VERSION 5.7 ;
  NOWIREEXTENSIONATPIN ON ;
  DIVIDERCHAR "/" ;
  BUSBITCHARS "[]" ;
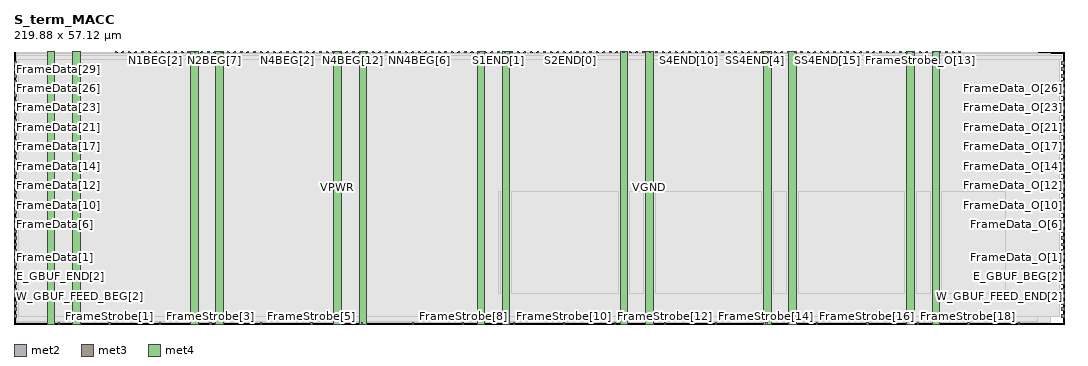
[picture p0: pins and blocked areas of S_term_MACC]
MACRO S_term_MACC
  CLASS BLOCK ;
  FOREIGN S_term_MACC ;
  ORIGIN 0.000 0.000 ;
  SIZE 219.880 BY 57.120 ;
  PIN CO
    DIRECTION OUTPUT ;
    USE SIGNAL ;
    PORT
      LAYER met2 ;
        RECT 98.530 56.840 98.810 57.120 ;
    END
  END CO
  PIN E_GBUF_BEG[0]
    DIRECTION OUTPUT ;
    USE SIGNAL ;
    ANTENNADIFFAREA 0.702900 ;
    PORT
      LAYER met3 ;
        RECT 219.280 6.840 219.880 7.440 ;
    END
  END E_GBUF_BEG[0]
  PIN E_GBUF_BEG[1]
    DIRECTION OUTPUT ;
    USE SIGNAL ;
    ANTENNADIFFAREA 0.702900 ;
    PORT
      LAYER met3 ;
        RECT 219.280 8.200 219.880 8.800 ;
    END
  END E_GBUF_BEG[1]
  PIN E_GBUF_BEG[2]
    DIRECTION OUTPUT ;
    USE SIGNAL ;
    ANTENNADIFFAREA 0.702900 ;
    PORT
      LAYER met3 ;
        RECT 219.280 9.560 219.880 10.160 ;
    END
  END E_GBUF_BEG[2]
  PIN E_GBUF_BEG[3]
    DIRECTION OUTPUT ;
    USE SIGNAL ;
    ANTENNADIFFAREA 0.702900 ;
    PORT
      LAYER met3 ;
        RECT 219.280 10.920 219.880 11.520 ;
    END
  END E_GBUF_BEG[3]
  PIN E_GBUF_END[0]
    DIRECTION INPUT ;
    USE SIGNAL ;
    ANTENNAGATEAREA 0.318000 ;
    PORT
      LAYER met3 ;
        RECT 0.000 6.840 0.600 7.440 ;
    END
  END E_GBUF_END[0]
  PIN E_GBUF_END[1]
    DIRECTION INPUT ;
    USE SIGNAL ;
    ANTENNAGATEAREA 0.318000 ;
    PORT
      LAYER met3 ;
        RECT 0.000 8.200 0.600 8.800 ;
    END
  END E_GBUF_END[1]
  PIN E_GBUF_END[2]
    DIRECTION INPUT ;
    USE SIGNAL ;
    ANTENNAGATEAREA 0.318000 ;
    PORT
      LAYER met3 ;
        RECT 0.000 9.560 0.600 10.160 ;
    END
  END E_GBUF_END[2]
  PIN E_GBUF_END[3]
    DIRECTION INPUT ;
    USE SIGNAL ;
    ANTENNAGATEAREA 0.318000 ;
    PORT
      LAYER met3 ;
        RECT 0.000 10.920 0.600 11.520 ;
    END
  END E_GBUF_END[3]
  PIN FrameData[0]
    DIRECTION INPUT ;
    USE SIGNAL ;
    ANTENNAGATEAREA 0.159000 ;
    PORT
      LAYER met3 ;
        RECT 0.000 12.280 0.600 12.880 ;
    END
  END FrameData[0]
  PIN FrameData[10]
    DIRECTION INPUT ;
    USE SIGNAL ;
    ANTENNAGATEAREA 0.159000 ;
    PORT
      LAYER met3 ;
        RECT 0.000 25.880 0.600 26.480 ;
    END
  END FrameData[10]
  PIN FrameData[11]
    DIRECTION INPUT ;
    USE SIGNAL ;
    ANTENNAGATEAREA 0.159000 ;
    PORT
      LAYER met3 ;
        RECT 0.000 27.240 0.600 27.840 ;
    END
  END FrameData[11]
  PIN FrameData[12]
    DIRECTION INPUT ;
    USE SIGNAL ;
    ANTENNAGATEAREA 0.159000 ;
    PORT
      LAYER met3 ;
        RECT 0.000 28.600 0.600 29.200 ;
    END
  END FrameData[12]
  PIN FrameData[13]
    DIRECTION INPUT ;
    USE SIGNAL ;
    ANTENNAGATEAREA 0.159000 ;
    PORT
      LAYER met3 ;
        RECT 0.000 29.960 0.600 30.560 ;
    END
  END FrameData[13]
  PIN FrameData[14]
    DIRECTION INPUT ;
    USE SIGNAL ;
    ANTENNAGATEAREA 0.159000 ;
    PORT
      LAYER met3 ;
        RECT 0.000 31.320 0.600 31.920 ;
    END
  END FrameData[14]
  PIN FrameData[15]
    DIRECTION INPUT ;
    USE SIGNAL ;
    ANTENNAGATEAREA 0.159000 ;
    PORT
      LAYER met3 ;
        RECT 0.000 32.680 0.600 33.280 ;
    END
  END FrameData[15]
  PIN FrameData[16]
    DIRECTION INPUT ;
    USE SIGNAL ;
    ANTENNAGATEAREA 0.159000 ;
    PORT
      LAYER met3 ;
        RECT 0.000 34.040 0.600 34.640 ;
    END
  END FrameData[16]
  PIN FrameData[17]
    DIRECTION INPUT ;
    USE SIGNAL ;
    ANTENNAGATEAREA 0.159000 ;
    PORT
      LAYER met3 ;
        RECT 0.000 35.400 0.600 36.000 ;
    END
  END FrameData[17]
  PIN FrameData[18]
    DIRECTION INPUT ;
    USE SIGNAL ;
    ANTENNAGATEAREA 0.159000 ;
    PORT
      LAYER met3 ;
        RECT 0.000 36.760 0.600 37.360 ;
    END
  END FrameData[18]
  PIN FrameData[19]
    DIRECTION INPUT ;
    USE SIGNAL ;
    ANTENNAGATEAREA 0.159000 ;
    PORT
      LAYER met3 ;
        RECT 0.000 38.120 0.600 38.720 ;
    END
  END FrameData[19]
  PIN FrameData[1]
    DIRECTION INPUT ;
    USE SIGNAL ;
    ANTENNAGATEAREA 0.159000 ;
    PORT
      LAYER met3 ;
        RECT 0.000 13.640 0.600 14.240 ;
    END
  END FrameData[1]
  PIN FrameData[20]
    DIRECTION INPUT ;
    USE SIGNAL ;
    ANTENNAGATEAREA 0.159000 ;
    PORT
      LAYER met3 ;
        RECT 0.000 39.480 0.600 40.080 ;
    END
  END FrameData[20]
  PIN FrameData[21]
    DIRECTION INPUT ;
    USE SIGNAL ;
    ANTENNAGATEAREA 0.159000 ;
    PORT
      LAYER met3 ;
        RECT 0.000 40.840 0.600 41.440 ;
    END
  END FrameData[21]
  PIN FrameData[22]
    DIRECTION INPUT ;
    USE SIGNAL ;
    ANTENNAGATEAREA 0.159000 ;
    PORT
      LAYER met3 ;
        RECT 0.000 42.200 0.600 42.800 ;
    END
  END FrameData[22]
  PIN FrameData[23]
    DIRECTION INPUT ;
    USE SIGNAL ;
    ANTENNAGATEAREA 0.159000 ;
    PORT
      LAYER met3 ;
        RECT 0.000 43.560 0.600 44.160 ;
    END
  END FrameData[23]
  PIN FrameData[24]
    DIRECTION INPUT ;
    USE SIGNAL ;
    ANTENNAGATEAREA 1.187400 ;
    ANTENNADIFFAREA 0.869400 ;
    PORT
      LAYER met3 ;
        RECT 0.000 44.920 0.600 45.520 ;
    END
  END FrameData[24]
  PIN FrameData[25]
    DIRECTION INPUT ;
    USE SIGNAL ;
    ANTENNAGATEAREA 1.187400 ;
    ANTENNADIFFAREA 0.869400 ;
    PORT
      LAYER met3 ;
        RECT 0.000 46.280 0.600 46.880 ;
    END
  END FrameData[25]
  PIN FrameData[26]
    DIRECTION INPUT ;
    USE SIGNAL ;
    ANTENNAGATEAREA 1.187400 ;
    ANTENNADIFFAREA 0.869400 ;
    PORT
      LAYER met3 ;
        RECT 0.000 47.640 0.600 48.240 ;
    END
  END FrameData[26]
  PIN FrameData[27]
    DIRECTION INPUT ;
    USE SIGNAL ;
    ANTENNAGATEAREA 1.187400 ;
    ANTENNADIFFAREA 0.869400 ;
    PORT
      LAYER met3 ;
        RECT 0.000 49.000 0.600 49.600 ;
    END
  END FrameData[27]
  PIN FrameData[28]
    DIRECTION INPUT ;
    USE SIGNAL ;
    ANTENNAGATEAREA 0.318000 ;
    PORT
      LAYER met3 ;
        RECT 0.000 50.360 0.600 50.960 ;
    END
  END FrameData[28]
  PIN FrameData[29]
    DIRECTION INPUT ;
    USE SIGNAL ;
    ANTENNAGATEAREA 1.187400 ;
    ANTENNADIFFAREA 0.869400 ;
    PORT
      LAYER met3 ;
        RECT 0.000 51.720 0.600 52.320 ;
    END
  END FrameData[29]
  PIN FrameData[2]
    DIRECTION INPUT ;
    USE SIGNAL ;
    ANTENNAGATEAREA 0.159000 ;
    PORT
      LAYER met3 ;
        RECT 0.000 15.000 0.600 15.600 ;
    END
  END FrameData[2]
  PIN FrameData[30]
    DIRECTION INPUT ;
    USE SIGNAL ;
    ANTENNAGATEAREA 1.187400 ;
    ANTENNADIFFAREA 0.869400 ;
    PORT
      LAYER met3 ;
        RECT 0.000 53.080 0.600 53.680 ;
    END
  END FrameData[30]
  PIN FrameData[31]
    DIRECTION INPUT ;
    USE SIGNAL ;
    ANTENNAGATEAREA 1.187400 ;
    ANTENNADIFFAREA 0.869400 ;
    PORT
      LAYER met3 ;
        RECT 0.000 54.440 0.600 55.040 ;
    END
  END FrameData[31]
  PIN FrameData[3]
    DIRECTION INPUT ;
    USE SIGNAL ;
    ANTENNAGATEAREA 0.159000 ;
    PORT
      LAYER met3 ;
        RECT 0.000 16.360 0.600 16.960 ;
    END
  END FrameData[3]
  PIN FrameData[4]
    DIRECTION INPUT ;
    USE SIGNAL ;
    ANTENNAGATEAREA 0.159000 ;
    PORT
      LAYER met3 ;
        RECT 0.000 17.720 0.600 18.320 ;
    END
  END FrameData[4]
  PIN FrameData[5]
    DIRECTION INPUT ;
    USE SIGNAL ;
    ANTENNAGATEAREA 0.159000 ;
    PORT
      LAYER met3 ;
        RECT 0.000 19.080 0.600 19.680 ;
    END
  END FrameData[5]
  PIN FrameData[6]
    DIRECTION INPUT ;
    USE SIGNAL ;
    ANTENNAGATEAREA 0.159000 ;
    PORT
      LAYER met3 ;
        RECT 0.000 20.440 0.600 21.040 ;
    END
  END FrameData[6]
  PIN FrameData[7]
    DIRECTION INPUT ;
    USE SIGNAL ;
    ANTENNAGATEAREA 0.159000 ;
    PORT
      LAYER met3 ;
        RECT 0.000 21.800 0.600 22.400 ;
    END
  END FrameData[7]
  PIN FrameData[8]
    DIRECTION INPUT ;
    USE SIGNAL ;
    ANTENNAGATEAREA 0.159000 ;
    PORT
      LAYER met3 ;
        RECT 0.000 23.160 0.600 23.760 ;
    END
  END FrameData[8]
  PIN FrameData[9]
    DIRECTION INPUT ;
    USE SIGNAL ;
    ANTENNAGATEAREA 0.159000 ;
    PORT
      LAYER met3 ;
        RECT 0.000 24.520 0.600 25.120 ;
    END
  END FrameData[9]
  PIN FrameData_O[0]
    DIRECTION OUTPUT ;
    USE SIGNAL ;
    ANTENNADIFFAREA 0.702900 ;
    PORT
      LAYER met3 ;
        RECT 219.280 12.280 219.880 12.880 ;
    END
  END FrameData_O[0]
  PIN FrameData_O[10]
    DIRECTION OUTPUT ;
    USE SIGNAL ;
    ANTENNADIFFAREA 0.702900 ;
    PORT
      LAYER met3 ;
        RECT 219.280 25.880 219.880 26.480 ;
    END
  END FrameData_O[10]
  PIN FrameData_O[11]
    DIRECTION OUTPUT ;
    USE SIGNAL ;
    ANTENNADIFFAREA 0.702900 ;
    PORT
      LAYER met3 ;
        RECT 219.280 27.240 219.880 27.840 ;
    END
  END FrameData_O[11]
  PIN FrameData_O[12]
    DIRECTION OUTPUT ;
    USE SIGNAL ;
    ANTENNADIFFAREA 0.702900 ;
    PORT
      LAYER met3 ;
        RECT 219.280 28.600 219.880 29.200 ;
    END
  END FrameData_O[12]
  PIN FrameData_O[13]
    DIRECTION OUTPUT ;
    USE SIGNAL ;
    ANTENNADIFFAREA 0.702900 ;
    PORT
      LAYER met3 ;
        RECT 219.280 29.960 219.880 30.560 ;
    END
  END FrameData_O[13]
  PIN FrameData_O[14]
    DIRECTION OUTPUT ;
    USE SIGNAL ;
    ANTENNADIFFAREA 0.702900 ;
    PORT
      LAYER met3 ;
        RECT 219.280 31.320 219.880 31.920 ;
    END
  END FrameData_O[14]
  PIN FrameData_O[15]
    DIRECTION OUTPUT ;
    USE SIGNAL ;
    ANTENNADIFFAREA 0.702900 ;
    PORT
      LAYER met3 ;
        RECT 219.280 32.680 219.880 33.280 ;
    END
  END FrameData_O[15]
  PIN FrameData_O[16]
    DIRECTION OUTPUT ;
    USE SIGNAL ;
    ANTENNADIFFAREA 0.702900 ;
    PORT
      LAYER met3 ;
        RECT 219.280 34.040 219.880 34.640 ;
    END
  END FrameData_O[16]
  PIN FrameData_O[17]
    DIRECTION OUTPUT ;
    USE SIGNAL ;
    ANTENNADIFFAREA 0.702900 ;
    PORT
      LAYER met3 ;
        RECT 219.280 35.400 219.880 36.000 ;
    END
  END FrameData_O[17]
  PIN FrameData_O[18]
    DIRECTION OUTPUT ;
    USE SIGNAL ;
    ANTENNADIFFAREA 0.702900 ;
    PORT
      LAYER met3 ;
        RECT 219.280 36.760 219.880 37.360 ;
    END
  END FrameData_O[18]
  PIN FrameData_O[19]
    DIRECTION OUTPUT ;
    USE SIGNAL ;
    ANTENNADIFFAREA 0.702900 ;
    PORT
      LAYER met3 ;
        RECT 219.280 38.120 219.880 38.720 ;
    END
  END FrameData_O[19]
  PIN FrameData_O[1]
    DIRECTION OUTPUT ;
    USE SIGNAL ;
    ANTENNADIFFAREA 0.702900 ;
    PORT
      LAYER met3 ;
        RECT 219.280 13.640 219.880 14.240 ;
    END
  END FrameData_O[1]
  PIN FrameData_O[20]
    DIRECTION OUTPUT ;
    USE SIGNAL ;
    ANTENNADIFFAREA 0.702900 ;
    PORT
      LAYER met3 ;
        RECT 219.280 39.480 219.880 40.080 ;
    END
  END FrameData_O[20]
  PIN FrameData_O[21]
    DIRECTION OUTPUT ;
    USE SIGNAL ;
    ANTENNADIFFAREA 0.702900 ;
    PORT
      LAYER met3 ;
        RECT 219.280 40.840 219.880 41.440 ;
    END
  END FrameData_O[21]
  PIN FrameData_O[22]
    DIRECTION OUTPUT ;
    USE SIGNAL ;
    ANTENNADIFFAREA 0.702900 ;
    PORT
      LAYER met3 ;
        RECT 219.280 42.200 219.880 42.800 ;
    END
  END FrameData_O[22]
  PIN FrameData_O[23]
    DIRECTION OUTPUT ;
    USE SIGNAL ;
    ANTENNADIFFAREA 0.702900 ;
    PORT
      LAYER met3 ;
        RECT 219.280 43.560 219.880 44.160 ;
    END
  END FrameData_O[23]
  PIN FrameData_O[24]
    DIRECTION OUTPUT ;
    USE SIGNAL ;
    ANTENNADIFFAREA 0.702900 ;
    PORT
      LAYER met3 ;
        RECT 219.280 44.920 219.880 45.520 ;
    END
  END FrameData_O[24]
  PIN FrameData_O[25]
    DIRECTION OUTPUT ;
    USE SIGNAL ;
    ANTENNADIFFAREA 0.702900 ;
    PORT
      LAYER met3 ;
        RECT 219.280 46.280 219.880 46.880 ;
    END
  END FrameData_O[25]
  PIN FrameData_O[26]
    DIRECTION OUTPUT ;
    USE SIGNAL ;
    ANTENNADIFFAREA 0.702900 ;
    PORT
      LAYER met3 ;
        RECT 219.280 47.640 219.880 48.240 ;
    END
  END FrameData_O[26]
  PIN FrameData_O[27]
    DIRECTION OUTPUT ;
    USE SIGNAL ;
    ANTENNADIFFAREA 0.702900 ;
    PORT
      LAYER met3 ;
        RECT 219.280 49.000 219.880 49.600 ;
    END
  END FrameData_O[27]
  PIN FrameData_O[28]
    DIRECTION OUTPUT ;
    USE SIGNAL ;
    ANTENNADIFFAREA 0.702900 ;
    PORT
      LAYER met3 ;
        RECT 219.280 50.360 219.880 50.960 ;
    END
  END FrameData_O[28]
  PIN FrameData_O[29]
    DIRECTION OUTPUT ;
    USE SIGNAL ;
    ANTENNADIFFAREA 0.702900 ;
    PORT
      LAYER met3 ;
        RECT 219.280 51.720 219.880 52.320 ;
    END
  END FrameData_O[29]
  PIN FrameData_O[2]
    DIRECTION OUTPUT ;
    USE SIGNAL ;
    ANTENNADIFFAREA 0.702900 ;
    PORT
      LAYER met3 ;
        RECT 219.280 15.000 219.880 15.600 ;
    END
  END FrameData_O[2]
  PIN FrameData_O[30]
    DIRECTION OUTPUT ;
    USE SIGNAL ;
    ANTENNADIFFAREA 0.702900 ;
    PORT
      LAYER met3 ;
        RECT 219.280 53.080 219.880 53.680 ;
    END
  END FrameData_O[30]
  PIN FrameData_O[31]
    DIRECTION OUTPUT ;
    USE SIGNAL ;
    ANTENNADIFFAREA 0.702900 ;
    PORT
      LAYER met3 ;
        RECT 219.280 54.440 219.880 55.040 ;
    END
  END FrameData_O[31]
  PIN FrameData_O[3]
    DIRECTION OUTPUT ;
    USE SIGNAL ;
    ANTENNADIFFAREA 0.702900 ;
    PORT
      LAYER met3 ;
        RECT 219.280 16.360 219.880 16.960 ;
    END
  END FrameData_O[3]
  PIN FrameData_O[4]
    DIRECTION OUTPUT ;
    USE SIGNAL ;
    ANTENNADIFFAREA 0.702900 ;
    PORT
      LAYER met3 ;
        RECT 219.280 17.720 219.880 18.320 ;
    END
  END FrameData_O[4]
  PIN FrameData_O[5]
    DIRECTION OUTPUT ;
    USE SIGNAL ;
    ANTENNADIFFAREA 0.702900 ;
    PORT
      LAYER met3 ;
        RECT 219.280 19.080 219.880 19.680 ;
    END
  END FrameData_O[5]
  PIN FrameData_O[6]
    DIRECTION OUTPUT ;
    USE SIGNAL ;
    ANTENNADIFFAREA 0.702900 ;
    PORT
      LAYER met3 ;
        RECT 219.280 20.440 219.880 21.040 ;
    END
  END FrameData_O[6]
  PIN FrameData_O[7]
    DIRECTION OUTPUT ;
    USE SIGNAL ;
    ANTENNADIFFAREA 0.702900 ;
    PORT
      LAYER met3 ;
        RECT 219.280 21.800 219.880 22.400 ;
    END
  END FrameData_O[7]
  PIN FrameData_O[8]
    DIRECTION OUTPUT ;
    USE SIGNAL ;
    ANTENNADIFFAREA 0.702900 ;
    PORT
      LAYER met3 ;
        RECT 219.280 23.160 219.880 23.760 ;
    END
  END FrameData_O[8]
  PIN FrameData_O[9]
    DIRECTION OUTPUT ;
    USE SIGNAL ;
    ANTENNADIFFAREA 0.702900 ;
    PORT
      LAYER met3 ;
        RECT 219.280 24.520 219.880 25.120 ;
    END
  END FrameData_O[9]
  PIN FrameStrobe[0]
    DIRECTION INPUT ;
    USE SIGNAL ;
    ANTENNAGATEAREA 1.431000 ;
    PORT
      LAYER met2 ;
        RECT 9.290 0.000 9.570 0.280 ;
    END
  END FrameStrobe[0]
  PIN FrameStrobe[10]
    DIRECTION INPUT ;
    USE SIGNAL ;
    ANTENNAGATEAREA 0.159000 ;
    PORT
      LAYER met2 ;
        RECT 115.090 0.000 115.370 0.280 ;
    END
  END FrameStrobe[10]
  PIN FrameStrobe[11]
    DIRECTION INPUT ;
    USE SIGNAL ;
    ANTENNAGATEAREA 0.159000 ;
    PORT
      LAYER met2 ;
        RECT 125.670 0.000 125.950 0.280 ;
    END
  END FrameStrobe[11]
  PIN FrameStrobe[12]
    DIRECTION INPUT ;
    USE SIGNAL ;
    ANTENNAGATEAREA 0.159000 ;
    PORT
      LAYER met2 ;
        RECT 136.250 0.000 136.530 0.280 ;
    END
  END FrameStrobe[12]
  PIN FrameStrobe[13]
    DIRECTION INPUT ;
    USE SIGNAL ;
    ANTENNAGATEAREA 0.159000 ;
    PORT
      LAYER met2 ;
        RECT 146.830 0.000 147.110 0.280 ;
    END
  END FrameStrobe[13]
  PIN FrameStrobe[14]
    DIRECTION INPUT ;
    USE SIGNAL ;
    ANTENNAGATEAREA 0.159000 ;
    PORT
      LAYER met2 ;
        RECT 157.410 0.000 157.690 0.280 ;
    END
  END FrameStrobe[14]
  PIN FrameStrobe[15]
    DIRECTION INPUT ;
    USE SIGNAL ;
    ANTENNAGATEAREA 0.159000 ;
    PORT
      LAYER met2 ;
        RECT 167.990 0.000 168.270 0.280 ;
    END
  END FrameStrobe[15]
  PIN FrameStrobe[16]
    DIRECTION INPUT ;
    USE SIGNAL ;
    ANTENNAGATEAREA 0.159000 ;
    PORT
      LAYER met2 ;
        RECT 178.570 0.000 178.850 0.280 ;
    END
  END FrameStrobe[16]
  PIN FrameStrobe[17]
    DIRECTION INPUT ;
    USE SIGNAL ;
    ANTENNAGATEAREA 0.159000 ;
    PORT
      LAYER met2 ;
        RECT 189.150 0.000 189.430 0.280 ;
    END
  END FrameStrobe[17]
  PIN FrameStrobe[18]
    DIRECTION INPUT ;
    USE SIGNAL ;
    ANTENNAGATEAREA 0.159000 ;
    PORT
      LAYER met2 ;
        RECT 199.730 0.000 200.010 0.280 ;
    END
  END FrameStrobe[18]
  PIN FrameStrobe[19]
    DIRECTION INPUT ;
    USE SIGNAL ;
    ANTENNAGATEAREA 0.159000 ;
    PORT
      LAYER met2 ;
        RECT 210.310 0.000 210.590 0.280 ;
    END
  END FrameStrobe[19]
  PIN FrameStrobe[1]
    DIRECTION INPUT ;
    USE SIGNAL ;
    ANTENNAGATEAREA 0.159000 ;
    PORT
      LAYER met2 ;
        RECT 19.870 0.000 20.150 0.280 ;
    END
  END FrameStrobe[1]
  PIN FrameStrobe[2]
    DIRECTION INPUT ;
    USE SIGNAL ;
    ANTENNAGATEAREA 0.159000 ;
    PORT
      LAYER met2 ;
        RECT 30.450 0.000 30.730 0.280 ;
    END
  END FrameStrobe[2]
  PIN FrameStrobe[3]
    DIRECTION INPUT ;
    USE SIGNAL ;
    ANTENNAGATEAREA 0.159000 ;
    PORT
      LAYER met2 ;
        RECT 41.030 0.000 41.310 0.280 ;
    END
  END FrameStrobe[3]
  PIN FrameStrobe[4]
    DIRECTION INPUT ;
    USE SIGNAL ;
    ANTENNAGATEAREA 0.159000 ;
    PORT
      LAYER met2 ;
        RECT 51.610 0.000 51.890 0.280 ;
    END
  END FrameStrobe[4]
  PIN FrameStrobe[5]
    DIRECTION INPUT ;
    USE SIGNAL ;
    ANTENNAGATEAREA 0.593700 ;
    ANTENNADIFFAREA 0.434700 ;
    PORT
      LAYER met2 ;
        RECT 62.190 0.000 62.470 0.280 ;
    END
  END FrameStrobe[5]
  PIN FrameStrobe[6]
    DIRECTION INPUT ;
    USE SIGNAL ;
    ANTENNAGATEAREA 0.593700 ;
    ANTENNADIFFAREA 0.434700 ;
    PORT
      LAYER met2 ;
        RECT 72.770 0.000 73.050 0.280 ;
    END
  END FrameStrobe[6]
  PIN FrameStrobe[7]
    DIRECTION INPUT ;
    USE SIGNAL ;
    ANTENNAGATEAREA 0.159000 ;
    PORT
      LAYER met2 ;
        RECT 83.350 0.000 83.630 0.280 ;
    END
  END FrameStrobe[7]
  PIN FrameStrobe[8]
    DIRECTION INPUT ;
    USE SIGNAL ;
    ANTENNAGATEAREA 0.159000 ;
    PORT
      LAYER met2 ;
        RECT 93.930 0.000 94.210 0.280 ;
    END
  END FrameStrobe[8]
  PIN FrameStrobe[9]
    DIRECTION INPUT ;
    USE SIGNAL ;
    ANTENNAGATEAREA 0.159000 ;
    PORT
      LAYER met2 ;
        RECT 104.510 0.000 104.790 0.280 ;
    END
  END FrameStrobe[9]
  PIN FrameStrobe_O[0]
    DIRECTION OUTPUT ;
    USE SIGNAL ;
    ANTENNADIFFAREA 0.702900 ;
    PORT
      LAYER met2 ;
        RECT 171.670 56.840 171.950 57.120 ;
    END
  END FrameStrobe_O[0]
  PIN FrameStrobe_O[10]
    DIRECTION OUTPUT ;
    USE SIGNAL ;
    ANTENNADIFFAREA 0.702900 ;
    PORT
      LAYER met2 ;
        RECT 185.470 56.840 185.750 57.120 ;
    END
  END FrameStrobe_O[10]
  PIN FrameStrobe_O[11]
    DIRECTION OUTPUT ;
    USE SIGNAL ;
    ANTENNADIFFAREA 0.702900 ;
    PORT
      LAYER met2 ;
        RECT 186.850 56.840 187.130 57.120 ;
    END
  END FrameStrobe_O[11]
  PIN FrameStrobe_O[12]
    DIRECTION OUTPUT ;
    USE SIGNAL ;
    ANTENNADIFFAREA 0.702900 ;
    PORT
      LAYER met2 ;
        RECT 188.230 56.840 188.510 57.120 ;
    END
  END FrameStrobe_O[12]
  PIN FrameStrobe_O[13]
    DIRECTION OUTPUT ;
    USE SIGNAL ;
    ANTENNADIFFAREA 0.702900 ;
    PORT
      LAYER met2 ;
        RECT 189.610 56.840 189.890 57.120 ;
    END
  END FrameStrobe_O[13]
  PIN FrameStrobe_O[14]
    DIRECTION OUTPUT ;
    USE SIGNAL ;
    ANTENNADIFFAREA 0.702900 ;
    PORT
      LAYER met2 ;
        RECT 190.990 56.840 191.270 57.120 ;
    END
  END FrameStrobe_O[14]
  PIN FrameStrobe_O[15]
    DIRECTION OUTPUT ;
    USE SIGNAL ;
    ANTENNADIFFAREA 0.702900 ;
    PORT
      LAYER met2 ;
        RECT 192.370 56.840 192.650 57.120 ;
    END
  END FrameStrobe_O[15]
  PIN FrameStrobe_O[16]
    DIRECTION OUTPUT ;
    USE SIGNAL ;
    ANTENNADIFFAREA 0.702900 ;
    PORT
      LAYER met2 ;
        RECT 193.750 56.840 194.030 57.120 ;
    END
  END FrameStrobe_O[16]
  PIN FrameStrobe_O[17]
    DIRECTION OUTPUT ;
    USE SIGNAL ;
    ANTENNADIFFAREA 0.702900 ;
    PORT
      LAYER met2 ;
        RECT 195.130 56.840 195.410 57.120 ;
    END
  END FrameStrobe_O[17]
  PIN FrameStrobe_O[18]
    DIRECTION OUTPUT ;
    USE SIGNAL ;
    ANTENNADIFFAREA 0.702900 ;
    PORT
      LAYER met2 ;
        RECT 196.510 56.840 196.790 57.120 ;
    END
  END FrameStrobe_O[18]
  PIN FrameStrobe_O[19]
    DIRECTION OUTPUT ;
    USE SIGNAL ;
    ANTENNADIFFAREA 0.702900 ;
    PORT
      LAYER met2 ;
        RECT 197.890 56.840 198.170 57.120 ;
    END
  END FrameStrobe_O[19]
  PIN FrameStrobe_O[1]
    DIRECTION OUTPUT ;
    USE SIGNAL ;
    ANTENNADIFFAREA 0.702900 ;
    PORT
      LAYER met2 ;
        RECT 173.050 56.840 173.330 57.120 ;
    END
  END FrameStrobe_O[1]
  PIN FrameStrobe_O[2]
    DIRECTION OUTPUT ;
    USE SIGNAL ;
    ANTENNADIFFAREA 0.702900 ;
    PORT
      LAYER met2 ;
        RECT 174.430 56.840 174.710 57.120 ;
    END
  END FrameStrobe_O[2]
  PIN FrameStrobe_O[3]
    DIRECTION OUTPUT ;
    USE SIGNAL ;
    ANTENNADIFFAREA 0.702900 ;
    PORT
      LAYER met2 ;
        RECT 175.810 56.840 176.090 57.120 ;
    END
  END FrameStrobe_O[3]
  PIN FrameStrobe_O[4]
    DIRECTION OUTPUT ;
    USE SIGNAL ;
    ANTENNADIFFAREA 0.702900 ;
    PORT
      LAYER met2 ;
        RECT 177.190 56.840 177.470 57.120 ;
    END
  END FrameStrobe_O[4]
  PIN FrameStrobe_O[5]
    DIRECTION OUTPUT ;
    USE SIGNAL ;
    ANTENNADIFFAREA 0.702900 ;
    PORT
      LAYER met2 ;
        RECT 178.570 56.840 178.850 57.120 ;
    END
  END FrameStrobe_O[5]
  PIN FrameStrobe_O[6]
    DIRECTION OUTPUT ;
    USE SIGNAL ;
    ANTENNADIFFAREA 0.702900 ;
    PORT
      LAYER met2 ;
        RECT 179.950 56.840 180.230 57.120 ;
    END
  END FrameStrobe_O[6]
  PIN FrameStrobe_O[7]
    DIRECTION OUTPUT ;
    USE SIGNAL ;
    ANTENNADIFFAREA 0.702900 ;
    PORT
      LAYER met2 ;
        RECT 181.330 56.840 181.610 57.120 ;
    END
  END FrameStrobe_O[7]
  PIN FrameStrobe_O[8]
    DIRECTION OUTPUT ;
    USE SIGNAL ;
    ANTENNADIFFAREA 0.702900 ;
    PORT
      LAYER met2 ;
        RECT 182.710 56.840 182.990 57.120 ;
    END
  END FrameStrobe_O[8]
  PIN FrameStrobe_O[9]
    DIRECTION OUTPUT ;
    USE SIGNAL ;
    ANTENNADIFFAREA 0.702900 ;
    PORT
      LAYER met2 ;
        RECT 184.090 56.840 184.370 57.120 ;
    END
  END FrameStrobe_O[9]
  PIN N1BEG[0]
    DIRECTION OUTPUT ;
    USE SIGNAL ;
    ANTENNADIFFAREA 0.702900 ;
    PORT
      LAYER met2 ;
        RECT 26.770 56.840 27.050 57.120 ;
    END
  END N1BEG[0]
  PIN N1BEG[1]
    DIRECTION OUTPUT ;
    USE SIGNAL ;
    ANTENNADIFFAREA 0.702900 ;
    PORT
      LAYER met2 ;
        RECT 28.150 56.840 28.430 57.120 ;
    END
  END N1BEG[1]
  PIN N1BEG[2]
    DIRECTION OUTPUT ;
    USE SIGNAL ;
    ANTENNADIFFAREA 0.702900 ;
    PORT
      LAYER met2 ;
        RECT 29.530 56.840 29.810 57.120 ;
    END
  END N1BEG[2]
  PIN N1BEG[3]
    DIRECTION OUTPUT ;
    USE SIGNAL ;
    ANTENNADIFFAREA 0.702900 ;
    PORT
      LAYER met2 ;
        RECT 30.910 56.840 31.190 57.120 ;
    END
  END N1BEG[3]
  PIN N2BEG[0]
    DIRECTION OUTPUT ;
    USE SIGNAL ;
    ANTENNADIFFAREA 0.702900 ;
    PORT
      LAYER met2 ;
        RECT 32.290 56.840 32.570 57.120 ;
    END
  END N2BEG[0]
  PIN N2BEG[1]
    DIRECTION OUTPUT ;
    USE SIGNAL ;
    ANTENNADIFFAREA 0.702900 ;
    PORT
      LAYER met2 ;
        RECT 33.670 56.840 33.950 57.120 ;
    END
  END N2BEG[1]
  PIN N2BEG[2]
    DIRECTION OUTPUT ;
    USE SIGNAL ;
    ANTENNADIFFAREA 0.702900 ;
    PORT
      LAYER met2 ;
        RECT 35.050 56.840 35.330 57.120 ;
    END
  END N2BEG[2]
  PIN N2BEG[3]
    DIRECTION OUTPUT ;
    USE SIGNAL ;
    ANTENNADIFFAREA 0.702900 ;
    PORT
      LAYER met2 ;
        RECT 36.430 56.840 36.710 57.120 ;
    END
  END N2BEG[3]
  PIN N2BEG[4]
    DIRECTION OUTPUT ;
    USE SIGNAL ;
    ANTENNADIFFAREA 0.702900 ;
    PORT
      LAYER met2 ;
        RECT 37.810 56.840 38.090 57.120 ;
    END
  END N2BEG[4]
  PIN N2BEG[5]
    DIRECTION OUTPUT ;
    USE SIGNAL ;
    ANTENNADIFFAREA 0.702900 ;
    PORT
      LAYER met2 ;
        RECT 39.190 56.840 39.470 57.120 ;
    END
  END N2BEG[5]
  PIN N2BEG[6]
    DIRECTION OUTPUT ;
    USE SIGNAL ;
    ANTENNADIFFAREA 0.702900 ;
    PORT
      LAYER met2 ;
        RECT 40.570 56.840 40.850 57.120 ;
    END
  END N2BEG[6]
  PIN N2BEG[7]
    DIRECTION OUTPUT ;
    USE SIGNAL ;
    ANTENNADIFFAREA 0.702900 ;
    PORT
      LAYER met2 ;
        RECT 41.950 56.840 42.230 57.120 ;
    END
  END N2BEG[7]
  PIN N2BEGb[0]
    DIRECTION OUTPUT ;
    USE SIGNAL ;
    ANTENNADIFFAREA 0.702900 ;
    PORT
      LAYER met2 ;
        RECT 43.330 56.840 43.610 57.120 ;
    END
  END N2BEGb[0]
  PIN N2BEGb[1]
    DIRECTION OUTPUT ;
    USE SIGNAL ;
    ANTENNADIFFAREA 0.702900 ;
    PORT
      LAYER met2 ;
        RECT 44.710 56.840 44.990 57.120 ;
    END
  END N2BEGb[1]
  PIN N2BEGb[2]
    DIRECTION OUTPUT ;
    USE SIGNAL ;
    ANTENNADIFFAREA 0.702900 ;
    PORT
      LAYER met2 ;
        RECT 46.090 56.840 46.370 57.120 ;
    END
  END N2BEGb[2]
  PIN N2BEGb[3]
    DIRECTION OUTPUT ;
    USE SIGNAL ;
    ANTENNADIFFAREA 0.702900 ;
    PORT
      LAYER met2 ;
        RECT 47.470 56.840 47.750 57.120 ;
    END
  END N2BEGb[3]
  PIN N2BEGb[4]
    DIRECTION OUTPUT ;
    USE SIGNAL ;
    ANTENNADIFFAREA 0.702900 ;
    PORT
      LAYER met2 ;
        RECT 48.850 56.840 49.130 57.120 ;
    END
  END N2BEGb[4]
  PIN N2BEGb[5]
    DIRECTION OUTPUT ;
    USE SIGNAL ;
    ANTENNADIFFAREA 0.702900 ;
    PORT
      LAYER met2 ;
        RECT 50.230 56.840 50.510 57.120 ;
    END
  END N2BEGb[5]
  PIN N2BEGb[6]
    DIRECTION OUTPUT ;
    USE SIGNAL ;
    ANTENNADIFFAREA 0.702900 ;
    PORT
      LAYER met2 ;
        RECT 51.610 56.840 51.890 57.120 ;
    END
  END N2BEGb[6]
  PIN N2BEGb[7]
    DIRECTION OUTPUT ;
    USE SIGNAL ;
    ANTENNADIFFAREA 0.702900 ;
    PORT
      LAYER met2 ;
        RECT 52.990 56.840 53.270 57.120 ;
    END
  END N2BEGb[7]
  PIN N4BEG[0]
    DIRECTION OUTPUT ;
    USE SIGNAL ;
    ANTENNADIFFAREA 0.702900 ;
    PORT
      LAYER met2 ;
        RECT 54.370 56.840 54.650 57.120 ;
    END
  END N4BEG[0]
  PIN N4BEG[10]
    DIRECTION OUTPUT ;
    USE SIGNAL ;
    ANTENNADIFFAREA 0.702900 ;
    PORT
      LAYER met2 ;
        RECT 68.170 56.840 68.450 57.120 ;
    END
  END N4BEG[10]
  PIN N4BEG[11]
    DIRECTION OUTPUT ;
    USE SIGNAL ;
    ANTENNADIFFAREA 0.702900 ;
    PORT
      LAYER met2 ;
        RECT 69.550 56.840 69.830 57.120 ;
    END
  END N4BEG[11]
  PIN N4BEG[12]
    DIRECTION OUTPUT ;
    USE SIGNAL ;
    ANTENNADIFFAREA 0.702900 ;
    PORT
      LAYER met2 ;
        RECT 70.930 56.840 71.210 57.120 ;
    END
  END N4BEG[12]
  PIN N4BEG[13]
    DIRECTION OUTPUT ;
    USE SIGNAL ;
    ANTENNADIFFAREA 0.702900 ;
    PORT
      LAYER met2 ;
        RECT 72.310 56.840 72.590 57.120 ;
    END
  END N4BEG[13]
  PIN N4BEG[14]
    DIRECTION OUTPUT ;
    USE SIGNAL ;
    ANTENNADIFFAREA 0.702900 ;
    PORT
      LAYER met2 ;
        RECT 73.690 56.840 73.970 57.120 ;
    END
  END N4BEG[14]
  PIN N4BEG[15]
    DIRECTION OUTPUT ;
    USE SIGNAL ;
    ANTENNADIFFAREA 0.702900 ;
    PORT
      LAYER met2 ;
        RECT 75.070 56.840 75.350 57.120 ;
    END
  END N4BEG[15]
  PIN N4BEG[1]
    DIRECTION OUTPUT ;
    USE SIGNAL ;
    ANTENNADIFFAREA 0.702900 ;
    PORT
      LAYER met2 ;
        RECT 55.750 56.840 56.030 57.120 ;
    END
  END N4BEG[1]
  PIN N4BEG[2]
    DIRECTION OUTPUT ;
    USE SIGNAL ;
    ANTENNADIFFAREA 0.702900 ;
    PORT
      LAYER met2 ;
        RECT 57.130 56.840 57.410 57.120 ;
    END
  END N4BEG[2]
  PIN N4BEG[3]
    DIRECTION OUTPUT ;
    USE SIGNAL ;
    ANTENNADIFFAREA 0.702900 ;
    PORT
      LAYER met2 ;
        RECT 58.510 56.840 58.790 57.120 ;
    END
  END N4BEG[3]
  PIN N4BEG[4]
    DIRECTION OUTPUT ;
    USE SIGNAL ;
    ANTENNADIFFAREA 0.702900 ;
    PORT
      LAYER met2 ;
        RECT 59.890 56.840 60.170 57.120 ;
    END
  END N4BEG[4]
  PIN N4BEG[5]
    DIRECTION OUTPUT ;
    USE SIGNAL ;
    ANTENNADIFFAREA 0.702900 ;
    PORT
      LAYER met2 ;
        RECT 61.270 56.840 61.550 57.120 ;
    END
  END N4BEG[5]
  PIN N4BEG[6]
    DIRECTION OUTPUT ;
    USE SIGNAL ;
    ANTENNADIFFAREA 0.702900 ;
    PORT
      LAYER met2 ;
        RECT 62.650 56.840 62.930 57.120 ;
    END
  END N4BEG[6]
  PIN N4BEG[7]
    DIRECTION OUTPUT ;
    USE SIGNAL ;
    ANTENNADIFFAREA 0.702900 ;
    PORT
      LAYER met2 ;
        RECT 64.030 56.840 64.310 57.120 ;
    END
  END N4BEG[7]
  PIN N4BEG[8]
    DIRECTION OUTPUT ;
    USE SIGNAL ;
    ANTENNADIFFAREA 0.702900 ;
    PORT
      LAYER met2 ;
        RECT 65.410 56.840 65.690 57.120 ;
    END
  END N4BEG[8]
  PIN N4BEG[9]
    DIRECTION OUTPUT ;
    USE SIGNAL ;
    ANTENNADIFFAREA 0.702900 ;
    PORT
      LAYER met2 ;
        RECT 66.790 56.840 67.070 57.120 ;
    END
  END N4BEG[9]
  PIN NN4BEG[0]
    DIRECTION OUTPUT ;
    USE SIGNAL ;
    ANTENNADIFFAREA 0.702900 ;
    PORT
      LAYER met2 ;
        RECT 76.450 56.840 76.730 57.120 ;
    END
  END NN4BEG[0]
  PIN NN4BEG[10]
    DIRECTION OUTPUT ;
    USE SIGNAL ;
    ANTENNADIFFAREA 0.702900 ;
    PORT
      LAYER met2 ;
        RECT 90.250 56.840 90.530 57.120 ;
    END
  END NN4BEG[10]
  PIN NN4BEG[11]
    DIRECTION OUTPUT ;
    USE SIGNAL ;
    ANTENNADIFFAREA 0.702900 ;
    PORT
      LAYER met2 ;
        RECT 91.630 56.840 91.910 57.120 ;
    END
  END NN4BEG[11]
  PIN NN4BEG[12]
    DIRECTION OUTPUT ;
    USE SIGNAL ;
    ANTENNADIFFAREA 0.702900 ;
    PORT
      LAYER met2 ;
        RECT 93.010 56.840 93.290 57.120 ;
    END
  END NN4BEG[12]
  PIN NN4BEG[13]
    DIRECTION OUTPUT ;
    USE SIGNAL ;
    ANTENNADIFFAREA 0.702900 ;
    PORT
      LAYER met2 ;
        RECT 94.390 56.840 94.670 57.120 ;
    END
  END NN4BEG[13]
  PIN NN4BEG[14]
    DIRECTION OUTPUT ;
    USE SIGNAL ;
    ANTENNADIFFAREA 0.702900 ;
    PORT
      LAYER met2 ;
        RECT 95.770 56.840 96.050 57.120 ;
    END
  END NN4BEG[14]
  PIN NN4BEG[15]
    DIRECTION OUTPUT ;
    USE SIGNAL ;
    ANTENNADIFFAREA 0.702900 ;
    PORT
      LAYER met2 ;
        RECT 97.150 56.840 97.430 57.120 ;
    END
  END NN4BEG[15]
  PIN NN4BEG[1]
    DIRECTION OUTPUT ;
    USE SIGNAL ;
    ANTENNADIFFAREA 0.702900 ;
    PORT
      LAYER met2 ;
        RECT 77.830 56.840 78.110 57.120 ;
    END
  END NN4BEG[1]
  PIN NN4BEG[2]
    DIRECTION OUTPUT ;
    USE SIGNAL ;
    ANTENNADIFFAREA 0.702900 ;
    PORT
      LAYER met2 ;
        RECT 79.210 56.840 79.490 57.120 ;
    END
  END NN4BEG[2]
  PIN NN4BEG[3]
    DIRECTION OUTPUT ;
    USE SIGNAL ;
    ANTENNADIFFAREA 0.702900 ;
    PORT
      LAYER met2 ;
        RECT 80.590 56.840 80.870 57.120 ;
    END
  END NN4BEG[3]
  PIN NN4BEG[4]
    DIRECTION OUTPUT ;
    USE SIGNAL ;
    ANTENNADIFFAREA 0.702900 ;
    PORT
      LAYER met2 ;
        RECT 81.970 56.840 82.250 57.120 ;
    END
  END NN4BEG[4]
  PIN NN4BEG[5]
    DIRECTION OUTPUT ;
    USE SIGNAL ;
    ANTENNADIFFAREA 0.702900 ;
    PORT
      LAYER met2 ;
        RECT 83.350 56.840 83.630 57.120 ;
    END
  END NN4BEG[5]
  PIN NN4BEG[6]
    DIRECTION OUTPUT ;
    USE SIGNAL ;
    ANTENNADIFFAREA 0.702900 ;
    PORT
      LAYER met2 ;
        RECT 84.730 56.840 85.010 57.120 ;
    END
  END NN4BEG[6]
  PIN NN4BEG[7]
    DIRECTION OUTPUT ;
    USE SIGNAL ;
    ANTENNADIFFAREA 0.702900 ;
    PORT
      LAYER met2 ;
        RECT 86.110 56.840 86.390 57.120 ;
    END
  END NN4BEG[7]
  PIN NN4BEG[8]
    DIRECTION OUTPUT ;
    USE SIGNAL ;
    ANTENNADIFFAREA 0.702900 ;
    PORT
      LAYER met2 ;
        RECT 87.490 56.840 87.770 57.120 ;
    END
  END NN4BEG[8]
  PIN NN4BEG[9]
    DIRECTION OUTPUT ;
    USE SIGNAL ;
    ANTENNADIFFAREA 0.702900 ;
    PORT
      LAYER met2 ;
        RECT 88.870 56.840 89.150 57.120 ;
    END
  END NN4BEG[9]
  PIN N_GBUF_BEG[0]
    DIRECTION OUTPUT ;
    USE SIGNAL ;
    ANTENNADIFFAREA 0.702900 ;
    PORT
      LAYER met2 ;
        RECT 21.250 56.840 21.530 57.120 ;
    END
  END N_GBUF_BEG[0]
  PIN N_GBUF_BEG[1]
    DIRECTION OUTPUT ;
    USE SIGNAL ;
    ANTENNADIFFAREA 0.702900 ;
    PORT
      LAYER met2 ;
        RECT 22.630 56.840 22.910 57.120 ;
    END
  END N_GBUF_BEG[1]
  PIN N_GBUF_BEG[2]
    DIRECTION OUTPUT ;
    USE SIGNAL ;
    ANTENNADIFFAREA 0.702900 ;
    PORT
      LAYER met2 ;
        RECT 24.010 56.840 24.290 57.120 ;
    END
  END N_GBUF_BEG[2]
  PIN N_GBUF_BEG[3]
    DIRECTION OUTPUT ;
    USE SIGNAL ;
    ANTENNADIFFAREA 0.702900 ;
    PORT
      LAYER met2 ;
        RECT 25.390 56.840 25.670 57.120 ;
    END
  END N_GBUF_BEG[3]
  PIN S1END[0]
    DIRECTION INPUT ;
    USE SIGNAL ;
    ANTENNAGATEAREA 0.318000 ;
    PORT
      LAYER met2 ;
        RECT 99.910 56.840 100.190 57.120 ;
    END
  END S1END[0]
  PIN S1END[1]
    DIRECTION INPUT ;
    USE SIGNAL ;
    ANTENNAGATEAREA 0.318000 ;
    PORT
      LAYER met2 ;
        RECT 101.290 56.840 101.570 57.120 ;
    END
  END S1END[1]
  PIN S1END[2]
    DIRECTION INPUT ;
    USE SIGNAL ;
    ANTENNAGATEAREA 0.318000 ;
    PORT
      LAYER met2 ;
        RECT 102.670 56.840 102.950 57.120 ;
    END
  END S1END[2]
  PIN S1END[3]
    DIRECTION INPUT ;
    USE SIGNAL ;
    ANTENNAGATEAREA 0.318000 ;
    PORT
      LAYER met2 ;
        RECT 104.050 56.840 104.330 57.120 ;
    END
  END S1END[3]
  PIN S2END[0]
    DIRECTION INPUT ;
    USE SIGNAL ;
    ANTENNAGATEAREA 0.159000 ;
    PORT
      LAYER met2 ;
        RECT 116.470 56.840 116.750 57.120 ;
    END
  END S2END[0]
  PIN S2END[1]
    DIRECTION INPUT ;
    USE SIGNAL ;
    ANTENNAGATEAREA 0.159000 ;
    PORT
      LAYER met2 ;
        RECT 117.850 56.840 118.130 57.120 ;
    END
  END S2END[1]
  PIN S2END[2]
    DIRECTION INPUT ;
    USE SIGNAL ;
    ANTENNAGATEAREA 0.159000 ;
    PORT
      LAYER met2 ;
        RECT 119.230 56.840 119.510 57.120 ;
    END
  END S2END[2]
  PIN S2END[3]
    DIRECTION INPUT ;
    USE SIGNAL ;
    ANTENNAGATEAREA 0.159000 ;
    PORT
      LAYER met2 ;
        RECT 120.610 56.840 120.890 57.120 ;
    END
  END S2END[3]
  PIN S2END[4]
    DIRECTION INPUT ;
    USE SIGNAL ;
    ANTENNAGATEAREA 0.318000 ;
    PORT
      LAYER met2 ;
        RECT 121.990 56.840 122.270 57.120 ;
    END
  END S2END[4]
  PIN S2END[5]
    DIRECTION INPUT ;
    USE SIGNAL ;
    ANTENNAGATEAREA 0.318000 ;
    PORT
      LAYER met2 ;
        RECT 123.370 56.840 123.650 57.120 ;
    END
  END S2END[5]
  PIN S2END[6]
    DIRECTION INPUT ;
    USE SIGNAL ;
    ANTENNAGATEAREA 0.318000 ;
    PORT
      LAYER met2 ;
        RECT 124.750 56.840 125.030 57.120 ;
    END
  END S2END[6]
  PIN S2END[7]
    DIRECTION INPUT ;
    USE SIGNAL ;
    ANTENNAGATEAREA 0.318000 ;
    PORT
      LAYER met2 ;
        RECT 126.130 56.840 126.410 57.120 ;
    END
  END S2END[7]
  PIN S2MID[0]
    DIRECTION INPUT ;
    USE SIGNAL ;
    ANTENNAGATEAREA 0.159000 ;
    PORT
      LAYER met2 ;
        RECT 105.430 56.840 105.710 57.120 ;
    END
  END S2MID[0]
  PIN S2MID[1]
    DIRECTION INPUT ;
    USE SIGNAL ;
    ANTENNAGATEAREA 0.159000 ;
    PORT
      LAYER met2 ;
        RECT 106.810 56.840 107.090 57.120 ;
    END
  END S2MID[1]
  PIN S2MID[2]
    DIRECTION INPUT ;
    USE SIGNAL ;
    ANTENNAGATEAREA 0.159000 ;
    PORT
      LAYER met2 ;
        RECT 108.190 56.840 108.470 57.120 ;
    END
  END S2MID[2]
  PIN S2MID[3]
    DIRECTION INPUT ;
    USE SIGNAL ;
    ANTENNAGATEAREA 0.159000 ;
    PORT
      LAYER met2 ;
        RECT 109.570 56.840 109.850 57.120 ;
    END
  END S2MID[3]
  PIN S2MID[4]
    DIRECTION INPUT ;
    USE SIGNAL ;
    ANTENNAGATEAREA 0.159000 ;
    PORT
      LAYER met2 ;
        RECT 110.950 56.840 111.230 57.120 ;
    END
  END S2MID[4]
  PIN S2MID[5]
    DIRECTION INPUT ;
    USE SIGNAL ;
    ANTENNAGATEAREA 0.159000 ;
    PORT
      LAYER met2 ;
        RECT 112.330 56.840 112.610 57.120 ;
    END
  END S2MID[5]
  PIN S2MID[6]
    DIRECTION INPUT ;
    USE SIGNAL ;
    ANTENNAGATEAREA 0.593700 ;
    ANTENNADIFFAREA 0.434700 ;
    PORT
      LAYER met2 ;
        RECT 113.710 56.840 113.990 57.120 ;
    END
  END S2MID[6]
  PIN S2MID[7]
    DIRECTION INPUT ;
    USE SIGNAL ;
    ANTENNAGATEAREA 0.593700 ;
    ANTENNADIFFAREA 0.434700 ;
    PORT
      LAYER met2 ;
        RECT 115.090 56.840 115.370 57.120 ;
    END
  END S2MID[7]
  PIN S4END[0]
    DIRECTION INPUT ;
    USE SIGNAL ;
    ANTENNAGATEAREA 0.318000 ;
    PORT
      LAYER met2 ;
        RECT 127.510 56.840 127.790 57.120 ;
    END
  END S4END[0]
  PIN S4END[10]
    DIRECTION INPUT ;
    USE SIGNAL ;
    ANTENNAGATEAREA 0.159000 ;
    PORT
      LAYER met2 ;
        RECT 141.310 56.840 141.590 57.120 ;
    END
  END S4END[10]
  PIN S4END[11]
    DIRECTION INPUT ;
    USE SIGNAL ;
    ANTENNAGATEAREA 0.159000 ;
    PORT
      LAYER met2 ;
        RECT 142.690 56.840 142.970 57.120 ;
    END
  END S4END[11]
  PIN S4END[12]
    DIRECTION INPUT ;
    USE SIGNAL ;
    ANTENNAGATEAREA 0.159000 ;
    PORT
      LAYER met2 ;
        RECT 144.070 56.840 144.350 57.120 ;
    END
  END S4END[12]
  PIN S4END[13]
    DIRECTION INPUT ;
    USE SIGNAL ;
    ANTENNAGATEAREA 0.159000 ;
    PORT
      LAYER met2 ;
        RECT 145.450 56.840 145.730 57.120 ;
    END
  END S4END[13]
  PIN S4END[14]
    DIRECTION INPUT ;
    USE SIGNAL ;
    ANTENNAGATEAREA 0.159000 ;
    PORT
      LAYER met2 ;
        RECT 146.830 56.840 147.110 57.120 ;
    END
  END S4END[14]
  PIN S4END[15]
    DIRECTION INPUT ;
    USE SIGNAL ;
    ANTENNAGATEAREA 0.159000 ;
    PORT
      LAYER met2 ;
        RECT 148.210 56.840 148.490 57.120 ;
    END
  END S4END[15]
  PIN S4END[1]
    DIRECTION INPUT ;
    USE SIGNAL ;
    ANTENNAGATEAREA 0.318000 ;
    PORT
      LAYER met2 ;
        RECT 128.890 56.840 129.170 57.120 ;
    END
  END S4END[1]
  PIN S4END[2]
    DIRECTION INPUT ;
    USE SIGNAL ;
    ANTENNAGATEAREA 0.318000 ;
    PORT
      LAYER met2 ;
        RECT 130.270 56.840 130.550 57.120 ;
    END
  END S4END[2]
  PIN S4END[3]
    DIRECTION INPUT ;
    USE SIGNAL ;
    ANTENNAGATEAREA 0.318000 ;
    PORT
      LAYER met2 ;
        RECT 131.650 56.840 131.930 57.120 ;
    END
  END S4END[3]
  PIN S4END[4]
    DIRECTION INPUT ;
    USE SIGNAL ;
    ANTENNAGATEAREA 0.159000 ;
    PORT
      LAYER met2 ;
        RECT 133.030 56.840 133.310 57.120 ;
    END
  END S4END[4]
  PIN S4END[5]
    DIRECTION INPUT ;
    USE SIGNAL ;
    ANTENNAGATEAREA 0.159000 ;
    PORT
      LAYER met2 ;
        RECT 134.410 56.840 134.690 57.120 ;
    END
  END S4END[5]
  PIN S4END[6]
    DIRECTION INPUT ;
    USE SIGNAL ;
    ANTENNAGATEAREA 0.159000 ;
    PORT
      LAYER met2 ;
        RECT 135.790 56.840 136.070 57.120 ;
    END
  END S4END[6]
  PIN S4END[7]
    DIRECTION INPUT ;
    USE SIGNAL ;
    ANTENNAGATEAREA 0.159000 ;
    PORT
      LAYER met2 ;
        RECT 137.170 56.840 137.450 57.120 ;
    END
  END S4END[7]
  PIN S4END[8]
    DIRECTION INPUT ;
    USE SIGNAL ;
    ANTENNAGATEAREA 0.159000 ;
    PORT
      LAYER met2 ;
        RECT 138.550 56.840 138.830 57.120 ;
    END
  END S4END[8]
  PIN S4END[9]
    DIRECTION INPUT ;
    USE SIGNAL ;
    ANTENNAGATEAREA 0.159000 ;
    PORT
      LAYER met2 ;
        RECT 139.930 56.840 140.210 57.120 ;
    END
  END S4END[9]
  PIN SS4END[0]
    DIRECTION INPUT ;
    USE SIGNAL ;
    ANTENNAGATEAREA 0.159000 ;
    PORT
      LAYER met2 ;
        RECT 149.590 56.840 149.870 57.120 ;
    END
  END SS4END[0]
  PIN SS4END[10]
    DIRECTION INPUT ;
    USE SIGNAL ;
    ANTENNAGATEAREA 0.159000 ;
    PORT
      LAYER met2 ;
        RECT 163.390 56.840 163.670 57.120 ;
    END
  END SS4END[10]
  PIN SS4END[11]
    DIRECTION INPUT ;
    USE SIGNAL ;
    ANTENNAGATEAREA 0.159000 ;
    PORT
      LAYER met2 ;
        RECT 164.770 56.840 165.050 57.120 ;
    END
  END SS4END[11]
  PIN SS4END[12]
    DIRECTION INPUT ;
    USE SIGNAL ;
    ANTENNAGATEAREA 0.159000 ;
    PORT
      LAYER met2 ;
        RECT 166.150 56.840 166.430 57.120 ;
    END
  END SS4END[12]
  PIN SS4END[13]
    DIRECTION INPUT ;
    USE SIGNAL ;
    ANTENNAGATEAREA 0.159000 ;
    PORT
      LAYER met2 ;
        RECT 167.530 56.840 167.810 57.120 ;
    END
  END SS4END[13]
  PIN SS4END[14]
    DIRECTION INPUT ;
    USE SIGNAL ;
    ANTENNAGATEAREA 0.159000 ;
    PORT
      LAYER met2 ;
        RECT 168.910 56.840 169.190 57.120 ;
    END
  END SS4END[14]
  PIN SS4END[15]
    DIRECTION INPUT ;
    USE SIGNAL ;
    ANTENNAGATEAREA 0.159000 ;
    PORT
      LAYER met2 ;
        RECT 170.290 56.840 170.570 57.120 ;
    END
  END SS4END[15]
  PIN SS4END[1]
    DIRECTION INPUT ;
    USE SIGNAL ;
    ANTENNAGATEAREA 0.159000 ;
    PORT
      LAYER met2 ;
        RECT 150.970 56.840 151.250 57.120 ;
    END
  END SS4END[1]
  PIN SS4END[2]
    DIRECTION INPUT ;
    USE SIGNAL ;
    ANTENNAGATEAREA 0.159000 ;
    PORT
      LAYER met2 ;
        RECT 152.350 56.840 152.630 57.120 ;
    END
  END SS4END[2]
  PIN SS4END[3]
    DIRECTION INPUT ;
    USE SIGNAL ;
    ANTENNAGATEAREA 0.159000 ;
    PORT
      LAYER met2 ;
        RECT 153.730 56.840 154.010 57.120 ;
    END
  END SS4END[3]
  PIN SS4END[4]
    DIRECTION INPUT ;
    USE SIGNAL ;
    ANTENNAGATEAREA 0.159000 ;
    PORT
      LAYER met2 ;
        RECT 155.110 56.840 155.390 57.120 ;
    END
  END SS4END[4]
  PIN SS4END[5]
    DIRECTION INPUT ;
    USE SIGNAL ;
    ANTENNAGATEAREA 0.159000 ;
    PORT
      LAYER met2 ;
        RECT 156.490 56.840 156.770 57.120 ;
    END
  END SS4END[5]
  PIN SS4END[6]
    DIRECTION INPUT ;
    USE SIGNAL ;
    ANTENNAGATEAREA 0.159000 ;
    PORT
      LAYER met2 ;
        RECT 157.870 56.840 158.150 57.120 ;
    END
  END SS4END[6]
  PIN SS4END[7]
    DIRECTION INPUT ;
    USE SIGNAL ;
    ANTENNAGATEAREA 0.159000 ;
    PORT
      LAYER met2 ;
        RECT 159.250 56.840 159.530 57.120 ;
    END
  END SS4END[7]
  PIN SS4END[8]
    DIRECTION INPUT ;
    USE SIGNAL ;
    ANTENNAGATEAREA 0.159000 ;
    PORT
      LAYER met2 ;
        RECT 160.630 56.840 160.910 57.120 ;
    END
  END SS4END[8]
  PIN SS4END[9]
    DIRECTION INPUT ;
    USE SIGNAL ;
    ANTENNAGATEAREA 0.159000 ;
    PORT
      LAYER met2 ;
        RECT 162.010 56.840 162.290 57.120 ;
    END
  END SS4END[9]
  PIN VGND
    DIRECTION INOUT ;
    USE GROUND ;
    PORT
      LAYER met4 ;
        RECT 12.260 0.000 13.860 57.120 ;
    END
    PORT
      LAYER met4 ;
        RECT 42.260 0.000 43.860 57.120 ;
    END
    PORT
      LAYER met4 ;
        RECT 72.260 0.000 73.860 57.120 ;
    END
    PORT
      LAYER met4 ;
        RECT 102.260 0.000 103.860 57.120 ;
    END
    PORT
      LAYER met4 ;
        RECT 132.260 0.000 133.860 57.120 ;
    END
    PORT
      LAYER met4 ;
        RECT 162.260 0.000 163.860 57.120 ;
    END
    PORT
      LAYER met4 ;
        RECT 192.260 0.000 193.860 57.120 ;
    END
  END VGND
  PIN VPWR
    DIRECTION INOUT ;
    USE POWER ;
    PORT
      LAYER met4 ;
        RECT 6.960 0.000 8.560 57.120 ;
    END
    PORT
      LAYER met4 ;
        RECT 36.960 0.000 38.560 57.120 ;
    END
    PORT
      LAYER met4 ;
        RECT 66.960 0.000 68.560 57.120 ;
    END
    PORT
      LAYER met4 ;
        RECT 96.960 0.000 98.560 57.120 ;
    END
    PORT
      LAYER met4 ;
        RECT 126.960 0.000 128.560 57.120 ;
    END
    PORT
      LAYER met4 ;
        RECT 156.960 0.000 158.560 57.120 ;
    END
    PORT
      LAYER met4 ;
        RECT 186.960 0.000 188.560 57.120 ;
    END
  END VPWR
  PIN W_GBUF_FEED_BEG[0]
    DIRECTION OUTPUT ;
    USE SIGNAL ;
    ANTENNADIFFAREA 0.702900 ;
    PORT
      LAYER met3 ;
        RECT 0.000 1.400 0.600 2.000 ;
    END
  END W_GBUF_FEED_BEG[0]
  PIN W_GBUF_FEED_BEG[1]
    DIRECTION OUTPUT ;
    USE SIGNAL ;
    ANTENNADIFFAREA 0.702900 ;
    PORT
      LAYER met3 ;
        RECT 0.000 2.760 0.600 3.360 ;
    END
  END W_GBUF_FEED_BEG[1]
  PIN W_GBUF_FEED_BEG[2]
    DIRECTION OUTPUT ;
    USE SIGNAL ;
    ANTENNADIFFAREA 0.702900 ;
    PORT
      LAYER met3 ;
        RECT 0.000 4.120 0.600 4.720 ;
    END
  END W_GBUF_FEED_BEG[2]
  PIN W_GBUF_FEED_BEG[3]
    DIRECTION OUTPUT ;
    USE SIGNAL ;
    ANTENNADIFFAREA 0.702900 ;
    PORT
      LAYER met3 ;
        RECT 0.000 5.480 0.600 6.080 ;
    END
  END W_GBUF_FEED_BEG[3]
  PIN W_GBUF_FEED_END[0]
    DIRECTION INPUT ;
    USE SIGNAL ;
    ANTENNAGATEAREA 0.593700 ;
    ANTENNADIFFAREA 0.434700 ;
    PORT
      LAYER met3 ;
        RECT 219.280 1.400 219.880 2.000 ;
    END
  END W_GBUF_FEED_END[0]
  PIN W_GBUF_FEED_END[1]
    DIRECTION INPUT ;
    USE SIGNAL ;
    ANTENNAGATEAREA 0.593700 ;
    ANTENNADIFFAREA 0.434700 ;
    PORT
      LAYER met3 ;
        RECT 219.280 2.760 219.880 3.360 ;
    END
  END W_GBUF_FEED_END[1]
  PIN W_GBUF_FEED_END[2]
    DIRECTION INPUT ;
    USE SIGNAL ;
    ANTENNAGATEAREA 0.593700 ;
    ANTENNADIFFAREA 0.434700 ;
    PORT
      LAYER met3 ;
        RECT 219.280 4.120 219.880 4.720 ;
    END
  END W_GBUF_FEED_END[2]
  PIN W_GBUF_FEED_END[3]
    DIRECTION INPUT ;
    USE SIGNAL ;
    ANTENNAGATEAREA 0.159000 ;
    PORT
      LAYER met3 ;
        RECT 219.280 5.480 219.880 6.080 ;
    END
  END W_GBUF_FEED_END[3]
  OBS
      LAYER nwell ;
        RECT 2.570 2.635 217.310 54.590 ;
      LAYER li1 ;
        RECT 2.760 2.635 217.120 54.485 ;
      LAYER met1 ;
        RECT 0.530 0.380 217.120 56.740 ;
      LAYER met2 ;
        RECT 0.550 56.560 20.970 56.850 ;
        RECT 21.810 56.560 22.350 56.850 ;
        RECT 23.190 56.560 23.730 56.850 ;
        RECT 24.570 56.560 25.110 56.850 ;
        RECT 25.950 56.560 26.490 56.850 ;
        RECT 27.330 56.560 27.870 56.850 ;
        RECT 28.710 56.560 29.250 56.850 ;
        RECT 30.090 56.560 30.630 56.850 ;
        RECT 31.470 56.560 32.010 56.850 ;
        RECT 32.850 56.560 33.390 56.850 ;
        RECT 34.230 56.560 34.770 56.850 ;
        RECT 35.610 56.560 36.150 56.850 ;
        RECT 36.990 56.560 37.530 56.850 ;
        RECT 38.370 56.560 38.910 56.850 ;
        RECT 39.750 56.560 40.290 56.850 ;
        RECT 41.130 56.560 41.670 56.850 ;
        RECT 42.510 56.560 43.050 56.850 ;
        RECT 43.890 56.560 44.430 56.850 ;
        RECT 45.270 56.560 45.810 56.850 ;
        RECT 46.650 56.560 47.190 56.850 ;
        RECT 48.030 56.560 48.570 56.850 ;
        RECT 49.410 56.560 49.950 56.850 ;
        RECT 50.790 56.560 51.330 56.850 ;
        RECT 52.170 56.560 52.710 56.850 ;
        RECT 53.550 56.560 54.090 56.850 ;
        RECT 54.930 56.560 55.470 56.850 ;
        RECT 56.310 56.560 56.850 56.850 ;
        RECT 57.690 56.560 58.230 56.850 ;
        RECT 59.070 56.560 59.610 56.850 ;
        RECT 60.450 56.560 60.990 56.850 ;
        RECT 61.830 56.560 62.370 56.850 ;
        RECT 63.210 56.560 63.750 56.850 ;
        RECT 64.590 56.560 65.130 56.850 ;
        RECT 65.970 56.560 66.510 56.850 ;
        RECT 67.350 56.560 67.890 56.850 ;
        RECT 68.730 56.560 69.270 56.850 ;
        RECT 70.110 56.560 70.650 56.850 ;
        RECT 71.490 56.560 72.030 56.850 ;
        RECT 72.870 56.560 73.410 56.850 ;
        RECT 74.250 56.560 74.790 56.850 ;
        RECT 75.630 56.560 76.170 56.850 ;
        RECT 77.010 56.560 77.550 56.850 ;
        RECT 78.390 56.560 78.930 56.850 ;
        RECT 79.770 56.560 80.310 56.850 ;
        RECT 81.150 56.560 81.690 56.850 ;
        RECT 82.530 56.560 83.070 56.850 ;
        RECT 83.910 56.560 84.450 56.850 ;
        RECT 85.290 56.560 85.830 56.850 ;
        RECT 86.670 56.560 87.210 56.850 ;
        RECT 88.050 56.560 88.590 56.850 ;
        RECT 89.430 56.560 89.970 56.850 ;
        RECT 90.810 56.560 91.350 56.850 ;
        RECT 92.190 56.560 92.730 56.850 ;
        RECT 93.570 56.560 94.110 56.850 ;
        RECT 94.950 56.560 95.490 56.850 ;
        RECT 96.330 56.560 96.870 56.850 ;
        RECT 97.710 56.560 98.250 56.850 ;
        RECT 99.090 56.560 99.630 56.850 ;
        RECT 100.470 56.560 101.010 56.850 ;
        RECT 101.850 56.560 102.390 56.850 ;
        RECT 103.230 56.560 103.770 56.850 ;
        RECT 104.610 56.560 105.150 56.850 ;
        RECT 105.990 56.560 106.530 56.850 ;
        RECT 107.370 56.560 107.910 56.850 ;
        RECT 108.750 56.560 109.290 56.850 ;
        RECT 110.130 56.560 110.670 56.850 ;
        RECT 111.510 56.560 112.050 56.850 ;
        RECT 112.890 56.560 113.430 56.850 ;
        RECT 114.270 56.560 114.810 56.850 ;
        RECT 115.650 56.560 116.190 56.850 ;
        RECT 117.030 56.560 117.570 56.850 ;
        RECT 118.410 56.560 118.950 56.850 ;
        RECT 119.790 56.560 120.330 56.850 ;
        RECT 121.170 56.560 121.710 56.850 ;
        RECT 122.550 56.560 123.090 56.850 ;
        RECT 123.930 56.560 124.470 56.850 ;
        RECT 125.310 56.560 125.850 56.850 ;
        RECT 126.690 56.560 127.230 56.850 ;
        RECT 128.070 56.560 128.610 56.850 ;
        RECT 129.450 56.560 129.990 56.850 ;
        RECT 130.830 56.560 131.370 56.850 ;
        RECT 132.210 56.560 132.750 56.850 ;
        RECT 133.590 56.560 134.130 56.850 ;
        RECT 134.970 56.560 135.510 56.850 ;
        RECT 136.350 56.560 136.890 56.850 ;
        RECT 137.730 56.560 138.270 56.850 ;
        RECT 139.110 56.560 139.650 56.850 ;
        RECT 140.490 56.560 141.030 56.850 ;
        RECT 141.870 56.560 142.410 56.850 ;
        RECT 143.250 56.560 143.790 56.850 ;
        RECT 144.630 56.560 145.170 56.850 ;
        RECT 146.010 56.560 146.550 56.850 ;
        RECT 147.390 56.560 147.930 56.850 ;
        RECT 148.770 56.560 149.310 56.850 ;
        RECT 150.150 56.560 150.690 56.850 ;
        RECT 151.530 56.560 152.070 56.850 ;
        RECT 152.910 56.560 153.450 56.850 ;
        RECT 154.290 56.560 154.830 56.850 ;
        RECT 155.670 56.560 156.210 56.850 ;
        RECT 157.050 56.560 157.590 56.850 ;
        RECT 158.430 56.560 158.970 56.850 ;
        RECT 159.810 56.560 160.350 56.850 ;
        RECT 161.190 56.560 161.730 56.850 ;
        RECT 162.570 56.560 163.110 56.850 ;
        RECT 163.950 56.560 164.490 56.850 ;
        RECT 165.330 56.560 165.870 56.850 ;
        RECT 166.710 56.560 167.250 56.850 ;
        RECT 168.090 56.560 168.630 56.850 ;
        RECT 169.470 56.560 170.010 56.850 ;
        RECT 170.850 56.560 171.390 56.850 ;
        RECT 172.230 56.560 172.770 56.850 ;
        RECT 173.610 56.560 174.150 56.850 ;
        RECT 174.990 56.560 175.530 56.850 ;
        RECT 176.370 56.560 176.910 56.850 ;
        RECT 177.750 56.560 178.290 56.850 ;
        RECT 179.130 56.560 179.670 56.850 ;
        RECT 180.510 56.560 181.050 56.850 ;
        RECT 181.890 56.560 182.430 56.850 ;
        RECT 183.270 56.560 183.810 56.850 ;
        RECT 184.650 56.560 185.190 56.850 ;
        RECT 186.030 56.560 186.570 56.850 ;
        RECT 187.410 56.560 187.950 56.850 ;
        RECT 188.790 56.560 189.330 56.850 ;
        RECT 190.170 56.560 190.710 56.850 ;
        RECT 191.550 56.560 192.090 56.850 ;
        RECT 192.930 56.560 193.470 56.850 ;
        RECT 194.310 56.560 194.850 56.850 ;
        RECT 195.690 56.560 196.230 56.850 ;
        RECT 197.070 56.560 197.610 56.850 ;
        RECT 198.450 56.560 214.270 56.850 ;
        RECT 0.550 0.560 214.270 56.560 ;
        RECT 0.550 0.270 9.010 0.560 ;
        RECT 9.850 0.270 19.590 0.560 ;
        RECT 20.430 0.270 30.170 0.560 ;
        RECT 31.010 0.270 40.750 0.560 ;
        RECT 41.590 0.270 51.330 0.560 ;
        RECT 52.170 0.270 61.910 0.560 ;
        RECT 62.750 0.270 72.490 0.560 ;
        RECT 73.330 0.270 83.070 0.560 ;
        RECT 83.910 0.270 93.650 0.560 ;
        RECT 94.490 0.270 104.230 0.560 ;
        RECT 105.070 0.270 114.810 0.560 ;
        RECT 115.650 0.270 125.390 0.560 ;
        RECT 126.230 0.270 135.970 0.560 ;
        RECT 136.810 0.270 146.550 0.560 ;
        RECT 147.390 0.270 157.130 0.560 ;
        RECT 157.970 0.270 167.710 0.560 ;
        RECT 168.550 0.270 178.290 0.560 ;
        RECT 179.130 0.270 188.870 0.560 ;
        RECT 189.710 0.270 199.450 0.560 ;
        RECT 200.290 0.270 210.030 0.560 ;
        RECT 210.870 0.270 214.270 0.560 ;
      LAYER met3 ;
        RECT 0.600 55.440 219.280 56.265 ;
        RECT 1.000 1.535 218.880 55.440 ;
      LAYER met4 ;
        RECT 101.495 6.295 101.860 27.705 ;
        RECT 104.260 6.295 126.560 27.705 ;
        RECT 128.960 6.295 131.860 27.705 ;
        RECT 134.260 6.295 156.560 27.705 ;
        RECT 158.960 6.295 161.860 27.705 ;
        RECT 164.260 6.295 186.560 27.705 ;
        RECT 188.960 6.295 191.860 27.705 ;
        RECT 194.260 6.295 207.625 27.705 ;
  END
END S_term_MACC
END LIBRARY

